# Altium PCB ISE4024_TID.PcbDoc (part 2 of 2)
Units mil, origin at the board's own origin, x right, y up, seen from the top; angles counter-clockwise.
Board outline 5000 x 4000 mil, 4 copper layers (Layer 1 - CIN1 - Top Layer, Layer 2 - SHLD1 - GND, Layer 3 - SHLD2 - PWR, Layer 4 - CIN2 - Bottom Layer), stack 61.434 mil thick; 132 components, 87 nets, 388 pads, 164 vias.

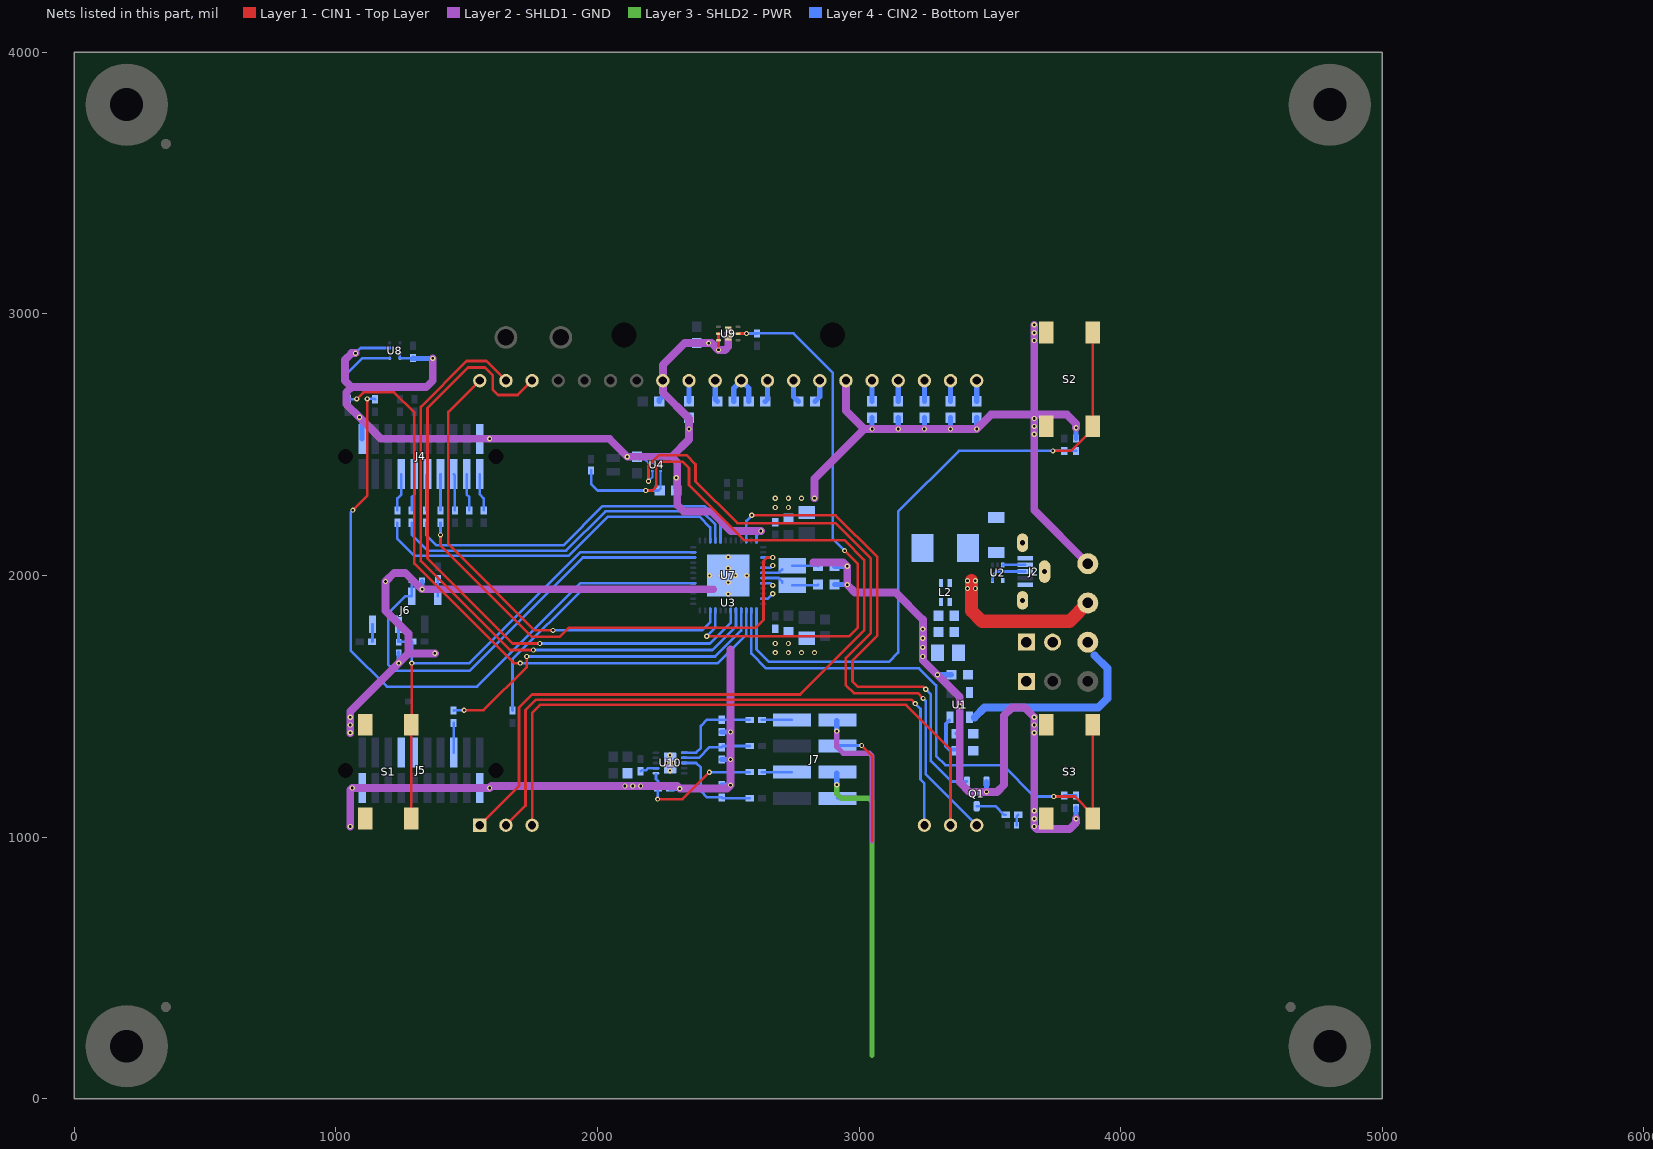
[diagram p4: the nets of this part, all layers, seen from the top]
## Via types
v1: diameter 20, hole 10, Layer 1 - CIN1 - Top Layer to Layer 4 - CIN2 - Bottom Layer, 151 vias
v2: diameter 19.68, hole 7.87, Layer 1 - CIN1 - Top Layer to Layer 4 - CIN2 - Bottom Layer, 13 vias

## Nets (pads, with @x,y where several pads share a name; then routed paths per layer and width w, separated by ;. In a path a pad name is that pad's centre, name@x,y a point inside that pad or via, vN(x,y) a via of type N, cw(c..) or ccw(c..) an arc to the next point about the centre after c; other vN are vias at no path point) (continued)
GND: C2.2 C3.2 C4.2 C6.2 C7.2 C9.2 C10.2 C12.2 C13.2 C14.2 C15.2 C16.2 C17.1 C18.1 C19.2 C20.1 C21.1 C22.2 C23.1 C24.1 C25.1 C26.2 C27.2 C28.1 C29.2 C30.2 C31.1 C32.1 C33.2 C34.1 C35.1 J4.2 J4.20 J5.1 J5.19 J6.5 L3.2 Q1.2 S1.3 S1.4 S2.3 S2.4 S3.3 S3.4 TP4.1 U1.2 U3.26 U3.33 U4.B3 U4.C2 U5.2 U6.2 U7.36 U7.41 U7.44 U7.47 U7.49 U8.B2 U8.C1 U8.D1 U9.2 U9.3 U9.7 U10.7 U10.11 | length 14443.8
  Layer 1 - CIN1 - Top Layer w10: v1(2462.6,2862.4) U9.3@2462.6,2899.21 U9.2@2462.6,2925
  Layer 2 - SHLD1 - GND w30: v1(1055,1040) 1055,1180 v1(1062.48,1187.48) v1(1587.52,1187.48) 1595.04,1195 v1(2105,1195) v1(2135,1195) v1(2165,1195) 2305,1195 v1(2315,1185) 2495,1185 v1(2508.62,1198.62) v1(2508.62,1296.38) v1(2508.62,1401.38) 2508.62,1716.38 ; v1(1055,1398.27) v1(1055,1428.27) v1(1055,1458.27) 1055,1480 v1(1240,1665) 1277.3,1702.3 ; v1(1075,2850) 1060,2850 1035,2825 1035,2745 1060,2720 ; v1(1370,2830) 1370,2745 1345,2720 1060,2720 ; v1(1378.38,1702.3) 1277.3,1702.3 ; 2442.13,1947.13 v1(1329.37,1947.13) 1327.87,1947.13 1265,2010 1222.87,2010 v1(1189.69,1976.81) 1189.69,1865.31 1277.3,1777.7 1277.3,1702.3 ; v2(2500,2925) 2500,2875 2487.4,2862.4 v1(2462.6,2862.4) 2436.5,2888.5 v1(2425,2888.5) 2333.5,2888.5 2250,2805 U3.33@2250,2745 2250,2700 2350,2600 v1(2350,2560) 2350,2520 2284,2454 ; v1(2625,2170) 2510,2170 2435,2245 2330,2245 2305,2270 2305,2433 2284,2454 ; 2825,2050 2940,2050 v1(2955,2035) v1(2955,1965) 2985,1935 3140,1935 3244,1831 v1(3244,1795) v1(3244,1760) v1(3244,1725) v1(3244,1690) 3244,1676.01 3385,1535.01 v1(3385,1500) 3385,1209.32 3421.91,1172.4 v1(3487.4,1172.4) 3527.4,1172.4 3555,1200 3555,1465 3585,1495 3633.27,1495 v1(3670,1458.27) v1(3670,1428.27) v1(3670,1398.27) v1(3670,1100) v1(3670,1070) v1(3670,1040) 3680.01,1030 3805,1030 3830,1055 v1(3830,1070) ; v1(2830,2295) 2830,2370 3020,2560 ; U3.26@2950,2745 2950,2630 3020,2560 ; v1(3670,2958.27) v1(3670,2928.27) v1(3670,2898.27) 3670,2615 ; v1(3830,2565) 3830,2580 3795,2615 3670,2615 ; TP4.1@3875,2045 3670,2250 v1(3670,2540) v1(3670,2570) v1(3670,2600) 3670,2615 ; 1060,2720 1040,2700 1040,2655 v1(1090,2605) 1172.48,2522.52 v1(1587.52,2522.52) 2045.48,2522.52 v1(2114,2454) 2284,2454 ; 3020,2560 v1(3050,2560) v1(3150,2560) v1(3250,2560) v1(3350,2560) v1(3450,2560) 3505,2615 3670,2615
  Layer 4 - CIN2 - Bottom Layer w4: U4.B3@2210,2430.75 U4.C2@2225.75,2415
  Layer 4 - CIN2 - Bottom Layer w8: C7.2@2160.12,2445 2180,2445 2194.25,2430.75 U4.B3@2210,2430.75
  Layer 4 - CIN2 - Bottom Layer w10: v1(1075,2850) 1094.85,2869.85 U8.B2@1205.31,2869.85 ; U8.C1@1244.68,2850.16 U8.D1@1244.68,2830.48 C28.1@1289.09,2830.48 ; C28.1@1289.09,2825.48 C28.1@1295,2831.38 ; C7.2@2150.75,2454.37 C7.2@2160.12,2445 ; C31.1@2165,1251.38 2168.62,1255 2185,1255 2193.32,1263.32 U10.7@2232,1263.32 ; U7.36@2608.27,2127 U7.36@2608.27,2133.86 2608.27,2153.27 v1(2625,2170) ; U7.47@2627,1911.42 2651.42,1911.42 v1(2670,1930) ; U7.44@2627,1970.47 2661.53,1970.47 v1(2670,1962) ; U7.41@2627,2029.53 2661.53,2029.53 v1(2670,2038)
  Layer 4 - CIN2 - Bottom Layer w15: v1(1240,1665) U6.2@1240,1705.32 ; C3.2@3373.5,1395 3385,1406.5 U1.2@3385,1457.76 v1(3385,1500)
  Layer 4 - CIN2 - Bottom Layer w20: v1(1062.48,1187.48) J5.19@1100,1187.48 ; v1(1090,2605) 1100,2595 J4.20@1100,2522.52 ; J6.5@1189.69,1919.96 v1(1189.69,1976.81) ; C28.1@1295,2831.38 1296.38,2830 v1(1370,2830) ; v1(1329.37,1947.13) U5.2@1329.37,1976.81 ; C23.1@1338.62,1702.3 v1(1378.38,1702.3) ; J5.1@1550,1187.48 v1(1587.52,1187.48) ; J4.2@1550,2522.52 v1(1587.52,2522.52) ; v1(2114,2454) 2150.38,2454 C7.2@2150.75,2454.37 ; C6.2@2236.5,2665 2236.5,2671.5 2250,2685 U3.33@2250,2745 ; C35.1@2278.62,1185 v1(2315,1185) ; C16.2@2301.5,2335 v1(2301.5,2373.5) ; v1(2350,2560) C9.2@2350,2603.5 ; C34.1@2475,1198.62 v1(2508.62,1198.62) ; C32.1@2475,1296.38 v1(2508.62,1296.38) ; C33.2@2475,1401.38 v1(2508.62,1401.38) ; C27.2@2906.5,1965 v1(2955,1965) ; C26.2@2906.5,2035 v1(2955,2035) ; v1(3050,2560) C10.2@3050,2603.5 ; v1(3150,2560) C12.2@3150,2603.5 ; v1(3250,2560) C13.2@3250,2603.5 ; v1(3300,1620) C4.2@3353.5,1620 ; v1(3350,2560) C14.2@3350,2603.5 ; v1(3450,2560) C15.2@3450,2603.5 ; v1(3487.4,1172.4) Q1.2@3487.4,1212.24 ; v1(3830,1070) C25.1@3830,1111.38 ; C24.1@3830,2523.62 v1(3830,2565)
  Layer 4 - CIN2 - Bottom Layer w25: C29.2@2380,2888.5 v1(2425,2888.5)
  other v1: 2680,1705 2730,1705 2780,1705 2830,1705 2680,1740 2730,1740 2680,2260 2730,2260 2680,2295 2730,2295 2780,2295
  other v2: 2277.82,1253.47 2264.04,1283 2291.6,1283 2277.82,1312.53 2500,1929.13 2500,1972.44 2429.13,2000 2472.44,2000 2527.56,2000 2570.87,2000 2500,2027.56 2500,2070.87
HDC_DRDY: R23.1 U7.3 U8.D2 | length 2730.7
  Layer 1 - CIN1 - Top Layer w10: v1(1080,2675) 1105,2700 1222.5,2700 1300,2622.5 1300,2045 1680,1665 v1(1705,1665)
  Layer 4 - CIN2 - Bottom Layer w10: v1(1080,2675) 1078.62,2673.62 R23.1@1045,2673.62 1045,2775 1100.48,2830.48 U8.D2@1205.31,2830.48 ; v1(1705,1665) 2460,1665 2568.9,1773.9 U7.3@2568.9,1873
HFXIN: C26.1 U7.42 Y1.1 | length 183.9
  Layer 4 - CIN2 - Bottom Layer w10: U7.42@2627,2009.84 2692.84,2009.84 Y1.1@2706,2023 ; Y1.1@2745,2037.4 2841.1,2037.4 C26.1@2843.5,2035
HFXOUT: C27.1 U7.43 Y1.2 | length 187.9
  Layer 4 - CIN2 - Bottom Layer w10: U7.43@2627,1990.16 2692.84,1990.16 2706,1977 Y1.2@2706,1973 ; Y1.2@2745,1962.6 2841.1,1962.6 C27.1@2843.5,1965
ILED: U3.20 U4.D3 | length 2583.7
  Layer 1 - CIN1 - Top Layer w10: v1(2195,2360) 2195,2420.06 2234.94,2460 2340,2460 2375,2425 2375,2360 2535,2200 2910,2200 3045,2065 3045,1780 2950,1685 2950,1580 2980,1550 3225,1550 v1(3245,1530)
  Layer 4 - CIN2 - Bottom Layer w8: v1(2195,2360) 2210,2375 U4.D3@2210,2399.25
  Layer 4 - CIN2 - Bottom Layer w10: v1(3245,1530) 3255,1520 3255,1240 U3.20@3450,1045
LCD_A0: U3.38 U7.6 | length 2518.4
  Layer 1 - CIN1 - Top Layer w10: U3.38@1750,2745 1695,2690 1620,2690 1600,2710 1600,2765 1570,2795 1505,2795 1350,2640 1350,2065 1675,1740 v1(1780,1740)
  Layer 4 - CIN2 - Bottom Layer w10: v1(1780,1740) 2430,1740 2509.84,1819.84 U7.6@2509.84,1873
LED_1: Q1.1 U7.34 | length 1917.9
  Layer 1 - CIN1 - Top Layer w10: v1(2590,2230) 2910,2230 3070,2070 3070,1770 2975,1675 2975,1595 2995,1575 3245,1575 v1(3255,1565)
  Layer 4 - CIN2 - Bottom Layer w10: U7.34@2568.9,2127 2568.9,2208.9 v1(2590,2230) ; v1(3255,1565) 3275,1545 3275,1290 3352.76,1212.24 Q1.1@3412.6,1212.24
LED_CA1: U3.2 U3.18 | length 2463.3
  Layer 1 - CIN1 - Top Layer w10: U3.2@1650,1045 1725,1120 1725,1485 1765,1525 3200,1525 v1(3215,1510)
  Layer 4 - CIN2 - Bottom Layer w10: v1(3215,1510) 3235,1490 3235,1220 3250,1205 U3.18@3250,1045
LED_CA2: U3.3 U3.19 | length 2402.8
  Layer 1 - CIN1 - Top Layer w10: U3.3@1750,1045 1750,1475 1780,1505 3180,1505 3350,1335 U3.19@3350,1045
NCSB_LCD: U3.40 U7.10 | length 1877.3
  Layer 1 - CIN1 - Top Layer w10: U3.40@1550,2745 1430,2625 1430,2120 1760,1790 v1(1830,1790)
  Layer 4 - CIN2 - Bottom Layer w10: v1(1830,1790) 2400,1790 2431.1,1821.1 U7.10@2431.1,1873
NCSB_RF: R12.2 U7.39 | length 1802
  Layer 1 - CIN1 - Top Layer w10: v1(1400,2155) 1400,2115 1750,1765 1855,1765 1890,1800 2605,1800 2635,1830 2635,2055 2648.9,2068.9 v1(2670,2068.9)
  Layer 4 - CIN2 - Bottom Layer w10: v1(1400,2155) R12.2@1400,2201.38 ; U7.39@2627,2068.9 U7.39@2633.86,2068.9 v1(2670,2068.9)
NetC2_1: C2.1 J1.1 L1.2
NetC4_1: C4.1 J3.1 U1.5
NetC5_1: C5.1 U3.31 | length 83.5
  Layer 4 - CIN2 - Bottom Layer w20: U3.31@2450,2745 2450,2673.5 C5.1@2458.5,2665
NetC5_2: C5.2 C8.1 U3.30 | length 183.6
  Layer 4 - CIN2 - Bottom Layer w20: C5.2@2521.5,2665 2521.5,2716.5 U3.30@2550,2745 2578.5,2716.5 C8.1@2578.5,2665
NetC8_2: C8.2 U3.29 | length 83.5
  Layer 4 - CIN2 - Bottom Layer w20: C8.2@2641.5,2665 2650,2673.5 U3.29@2650,2745
NetC9_1: C9.1 U3.32 | length 78.5
  Layer 4 - CIN2 - Bottom Layer w20: C9.1@2350,2666.5 U3.32@2350,2745
NetC10_1: C10.1 U3.25 | length 78.5
  Layer 4 - CIN2 - Bottom Layer w20: C10.1@3050,2666.5 U3.25@3050,2745
NetC11_1: C11.1 U3.28 | length 87.7
  Layer 4 - CIN2 - Bottom Layer w20: U3.28@2750,2745 2750,2683.5 C11.1@2768.5,2665
NetC11_2: C11.2 U3.27 | length 87.7
  Layer 4 - CIN2 - Bottom Layer w20: C11.2@2831.5,2665 2850,2683.5 U3.27@2850,2745
NetC12_1: C12.1 U3.24 | length 78.5
  Layer 4 - CIN2 - Bottom Layer w20: C12.1@3150,2666.5 U3.24@3150,2745
NetC13_1: C13.1 U3.23 | length 78.5
  Layer 4 - CIN2 - Bottom Layer w20: C13.1@3250,2666.5 U3.23@3250,2745
NetC14_1: C14.1 U3.22 | length 78.5
  Layer 4 - CIN2 - Bottom Layer w20: C14.1@3350,2666.5 U3.22@3350,2745
NetC15_1: C15.1 U3.21 | length 78.5
  Layer 4 - CIN2 - Bottom Layer w20: C15.1@3450,2666.5 U3.21@3450,2745
NetC32_2: C32.2 R24.2 U10.2 | length 276.6
  Layer 4 - CIN2 - Bottom Layer w10: U10.2@2324,1302.69 2387.69,1302.69 2428.62,1343.62 C32.2@2475,1343.62 2479.38,1348 R24.2@2581.88,1348
NetC33_1: C33.1 R25.1 U10.1 | length 360.2
  Layer 4 - CIN2 - Bottom Layer w10: U10.1@2324,1322.37 2377.37,1322.37 2395,1340 2395,1425 2418.62,1448.62 C33.1@2475,1448.62 2475.62,1448 R25.1@2581.88,1448
NetC34_2: C34.2 R26.2 U10.3 | length 366.5
  Layer 4 - CIN2 - Bottom Layer w10: U10.3@2324,1283 2377,1283 2395,1265 2395,1175 2418.62,1151.38 C34.2@2475,1151.38 2478.38,1148 R26.2@2581.88,1148
NetC35_2: C35.2 R27.1 U10.6 | length 493.3
  Layer 1 - CIN1 - Top Layer w10: v1(2230,1145) 2325,1145 v1(2428,1248)
  Layer 4 - CIN2 - Bottom Layer w10: U10.6@2223.69,1240 2223.69,1221.31 2231.38,1213.62 C35.2@2231.38,1185 2230,1183.62 v1(2230,1145) ; v1(2428,1248) R27.1@2581.88,1248
NetD3_1: D3.1 J5.12 J5.14
NetD4_1: D4.1 R21.2 | length 42.4
  Layer 4 - CIN2 - Bottom Layer w10: D4.1@3602.72,1045 3602.72,1079.09 R21.2@3608.62,1085
NetJ4_1: J4.1 R15.2 | length 145.1
  Layer 4 - CIN2 - Bottom Layer w10: J4.1@1550,2387.48 1550,2310 1565,2295 R15.2@1565,2248.62
NetJ4_3: J4.3 R14.1 | length 143
  Layer 4 - CIN2 - Bottom Layer w10: J4.3@1500,2387.48 1500,2310 1510,2300 R14.1@1510,2248.62
NetJ4_5: J4.5 R13.1 | length 140.9
  Layer 4 - CIN2 - Bottom Layer w10: J4.5@1450,2387.48 1455,2382.48 R13.1@1455,2248.62
NetJ4_7: J4.7 R12.1 | length 138.9
  Layer 4 - CIN2 - Bottom Layer w10: R12.1@1400,2248.62 J4.7@1400,2387.48
NetJ4_9: J4.9 R8.2 | length 140.9
  Layer 4 - CIN2 - Bottom Layer w10: R8.2@1345,2248.62 1345,2382.48 J4.9@1350,2387.48
NetJ4_11: J4.11 R7.2 | length 143
  Layer 4 - CIN2 - Bottom Layer w10: R7.2@1290,2248.62 1290,2300 1300,2310 J4.11@1300,2387.48
NetJ4_13: J4.13 R5.1 | length 145.1
  Layer 4 - CIN2 - Bottom Layer w10: R5.1@1235,2248.62 1235,2295 1250,2310 J4.13@1250,2387.48
NetJ5_6: J5.6 R11.1 | length 113.9
  Layer 4 - CIN2 - Bottom Layer w10: J5.6@1450,1322.52 R11.1@1450,1436.38
NetJ6_1: J6.1 R3.2 | length 73.2
  Layer 4 - CIN2 - Bottom Layer w10: J6.1@1389.69,1919.96 R3.2@1389.69,1993.19
NetJ6_6: J6.6 R9.2 | length 67.4
  Layer 4 - CIN2 - Bottom Layer w10: R9.2@1138.31,1746.81 1139.69,1748.19 J6.6@1139.69,1813.66
NetL1_1: L1.1 L2.3
NetL2_2: L2.2 L3.1
NetQ1_3: Q1.3 R21.1 | length 124.9
  Layer 4 - CIN2 - Bottom Layer w10: Q1.3@3450,1117.76 3522.24,1117.76 3555,1085 R21.1@3561.38,1085
NetR1_2: R1.2 U1.3 | length 148.4
  Layer 4 - CIN2 - Bottom Layer w15: U1.3@3345,1445 3333,1433 3333,1347 3345,1335 R1.2@3373.5,1335
NRST_EM: R11.2 U7.4 | length 1333
  Layer 1 - CIN1 - Top Layer w10: v1(1490,1485) 1565,1485 1730,1650 v1(1730,1690)
  Layer 4 - CIN2 - Bottom Layer w10: R11.2@1450,1483.62 1451.38,1485 v1(1490,1485) ; v1(1730,1690) 2450,1690 2549.21,1789.21 U7.4@2549.21,1873
NRST_LCD: U3.39 U7.5 | length 2469.5
  Layer 1 - CIN1 - Top Layer w10: U3.39@1650,2745 1575,2820 1500,2820 1325,2645 1325,2055 1665,1715 v1(1755,1715)
  Layer 4 - CIN2 - Bottom Layer w10: v1(1755,1715) 2440,1715 2529.53,1804.53 U7.5@2529.53,1873
OPT_INT: R22.1 U7.9 U9.5 | length 2149.8
  Layer 1 - CIN1 - Top Layer w10: v1(2417.5,1767.5) 2962.5,1767.5 2995,1800 2995,2045 v1(2945,2095) ; U9.5@2537.4,2925 v1(2570,2925)
  Layer 4 - CIN2 - Bottom Layer w10: v1(2417.5,1767.5) 2450.79,1800.79 U7.9@2450.79,1873 ; v1(2570,2925) 2609.39,2925 R22.1@2610,2925.61 2749.39,2925.61 2900,2775 2900,2140 v1(2945,2095)
OVP: C16.1 D2.1 U3.1 U4.D1 | length 3739.6
  Layer 1 - CIN1 - Top Layer w10: U3.1@1550,1045 1700,1195 1700,1495 1750,1545 2775,1545 3020,1790 3020,2060 2945,2135 2560,2135 2350,2345 2350,2410 2325,2435 2245,2435 2225,2415 2225,2340 2210,2325 v1(2185,2325)
  Layer 4 - CIN2 - Bottom Layer w8: C16.1@2241.5,2332.99 U4.D1@2241.5,2399.25
  Layer 4 - CIN2 - Bottom Layer w10: D2.1@1975.75,2401.22 1975.75,2349.25 2000,2325 v1(2185,2325) 2233.5,2325 C16.1@2241.5,2332.99
P3.4: R5.2 U7.27 | length 1420.5
  Layer 4 - CIN2 - Bottom Layer w10: R5.2@1235,2201.38 1235,2140 1300,2075 1890,2075 2040,2225 2390,2225 2431.1,2183.9 U7.27@2431.1,2127
P3.5: R7.1 U7.28 | length 1382.4
  Layer 4 - CIN2 - Bottom Layer w10: R7.1@1290,2201.38 1290,2155 1350,2095 1880,2095 2030,2245 2400,2245 2450.79,2194.21 U7.28@2450.79,2127
P3.6: R8.1 U7.29 | length 1353.1
  Layer 4 - CIN2 - Bottom Layer w10: R8.1@1345,2201.38 1345,2155 1385,2115 1870,2115 2020,2265 2410,2265 2470.47,2204.53 U7.29@2470.47,2127
SBWTCK: J6.3 U5.1 U7.22 | length 1736.7
  Layer 4 - CIN2 - Bottom Layer w10: U5.1@1290,1981.81 1289.69,1981.5 J6.3@1289.69,1919.96 1264.96,1919.96 1200,1855 1200,1660 1225,1635 1510,1635 1943.9,2068.9 U7.22@2373,2068.9
SBWTDIO: C23.2 J6.4 R18.1 S1.1 S1.2 U6.1 U7.23 | length 2055.2
  Layer 1 - CIN1 - Top Layer w10: S1.2@1288.58,1070.87 S1.1@1288.58,1429.13 1290,1430.55 v1(1290,1665)
  Layer 4 - CIN2 - Bottom Layer w10: J6.4@1239.69,1813.66 1239.37,1813.35 1239.37,1746.81 1239.86,1747.3 R18.1@1291.38,1747.3 C23.2@1291.38,1702.3 1290,1700.92 v1(1290,1665) 1510,1665 1933.58,2088.58 U7.23@2373,2088.58
SENSOR1: J7.3 | length 474.5
  Layer 1 - CIN1 - Top Layer w10: v1(3010,1350) 3050,1310 3050,985
  Layer 4 - CIN2 - Bottom Layer w10: J7.3@2917.9,1348 2919.9,1350 v1(3010,1350)
SENSOR2: J7.7 | length 1092.5
  Layer 4 - CIN2 - Bottom Layer w10: J7.7@2917.9,1148 3037,1148 3050,1135 3050,180
SHLD1: J7.2 R25.2 | length 114
  Layer 4 - CIN2 - Bottom Layer w10: R25.2@2629.12,1448 J7.2@2743.1,1448
SHLD1_1: J7.1 | length 578.7
  Layer 2 - SHLD1 - GND w20: v1(2915,1405) 2915,1345 2940,1320 3040,1320 3050,1310 3050,985
  Layer 4 - CIN2 - Bottom Layer w10: J7.1@2915,1445.1 J7.1@2917.9,1448
  Layer 4 - CIN2 - Bottom Layer w20: v1(2915,1405) J7.1@2915,1445.1
SHLD1_2: J7.5 | length 1201.6
  Layer 3 - SHLD2 - PWR w20: v1(2915,1200) 2915,1165 2932,1148 3037,1148 3050,1135 3050,165
  Layer 4 - CIN2 - Bottom Layer w10: J7.5@2915,1245.1 J7.5@2917.9,1248
  Layer 4 - CIN2 - Bottom Layer w20: v1(2915,1200) J7.5@2915,1245.1
SHLD2: J7.6 R27.2 | length 114
  Layer 4 - CIN2 - Bottom Layer w10: R27.2@2629.13,1248 J7.6@2743.1,1248
UART_CTS: R2.2 U7.17 | length 2556.5
  Layer 1 - CIN1 - Top Layer w10: v1(1065,2250) 1120,2305 v1(1120,2675)
  Layer 4 - CIN2 - Bottom Layer w10: v1(1065,2250) 1056,2241 1056,1714 1195,1575 1540,1575 1935.47,1970.47 U7.17@2373,1970.47 ; v1(1120,2675) 1148.62,2675 R2.2@1150,2673.62
UART_RTS: R10.1 U7.16 | length 1006.5
  Layer 4 - CIN2 - Bottom Layer w10: R10.1@1675,1483.62 1675,1680 1945.79,1950.79 U7.16@2373,1950.79
USB_D_N: J2.2 U2.3 | length 85.8
  Layer 4 - CIN2 - Bottom Layer w10: U2.3@3549.69,2039.53 3550.75,2040.59 J2.2@3635,2040.59
USB_D_P: J2.3 U2.5 | length 150.6
  Layer 4 - CIN2 - Bottom Layer w10: U2.5@3510.31,1980.47 3510.31,2000.31 3525,2015 J2.3@3635,2015
USB_GND: C1.2 D1.1 J2.5 J2.6 J2.7 J2.8 L2.1 U2.4
USR_BTN_1: C24.2 R19.1 S2.1 S2.2 U7.1 | length 2604.5
  Layer 1 - CIN1 - Top Layer w10: v1(3741.38,2476.38) 3811.38,2476.38 3893.58,2558.58 S2.2@3893.58,2570.86 S2.1@3893.58,2929.13
  Layer 4 - CIN2 - Bottom Layer w10: U7.1@2608.27,1873 2608.27,1716.73 2655,1670 3115,1670 3150,1705 3150,2245 3381.38,2476.38 v1(3741.38,2476.38) R19.1@3785,2476.38 C24.2@3830,2476.38
USR_BTN_2: C25.2 R20.1 S3.1 S3.2 U7.2 | length 2334.3
  Layer 1 - CIN1 - Top Layer w10: v1(3745,1155) 3825,1155 S3.2@3893.58,1086.42 ; S3.2@3893.58,1070.87 S3.2@3893.58,1086.42 ; S3.1@3893.58,1429.13 S3.2@3893.58,1086.42
  Layer 4 - CIN2 - Bottom Layer w10: U7.2@2588.58,1873 2588.58,1701.42 2645,1645 3230,1645 3295,1580 3295,1310 3330,1275 3550,1275 3670,1155 v1(3745,1155) 3781.38,1155 R20.1@3785,1158.62 C25.2@3830,1158.62
V_INPUT: C3.1 J1.2 R1.1 TP2.1 U1.1 | length 723.3
  Layer 4 - CIN2 - Bottom Layer w30: 3442.49,1457.49 3480,1495 3915,1495 3950,1530 3950,1645 3900,1695
VBUS: C1.1 D1.2 J2.1 L2.4 TP1.1 | length 605.6
  Layer 1 - CIN1 - Top Layer w50: 3430,1980 3430,1865 3470,1825 3805,1825 TP1.1@3875,1895
  other v1: 3415,1950 3445,1950 3415,1980 3445,1980
pads on no net: FID1.1 FID2.1 FID3.1 FID4.1 FID5.1 FID6.1 H1.1 H2.1 H3.1 H4.1 H5.0 H6.0 H7.0 H8.0 J2.4 J4.4 J4.6 J4.8 J4.10 J4.15 J4.16 J4.17 J4.19 J4.MH1 J4.MH2 J5.2 J5.4 J5.5 J5.7 J5.8 J5.9 J5.10 J5.11 J5.13 J5.15 J5.16 J5.17 J5.18 J5.20 J5.MH1 J5.MH2 SH-J1.0 SH-J2.0 SH-J3.0 SH-J4.0 SH-J5.0 SH-J6.0 U1.4 U2.1 U2.2 U4.B2 U4.D2 U7.8 U7.12 U7.13 U7.14 U7.15 U7.18 U7.19 U7.30 U7.33 U7.35 U7.38 U7.40 U7.45 U7.46 U8.C2 U10.4 U10.5

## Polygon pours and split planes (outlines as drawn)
NetC4_1 on Layer 4 - CIN2 - Bottom Layer "Layer 1 - CIN1 - Top Layer-No Net" (solid, remove dead copper, pour order 13): 3655,1645 3390,1645 3390,1545 3410,1525 3655,1525 3675,1545 3675,1625
GND on Layer 2 - SHLD1 - GND "Layer 2 - SHLD1 - GND-GND" (solid, remove dead copper, pour order 5): 3005,1655 2375,1655 2375,2310 3005,2310

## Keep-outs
Keep-Out Layer:
  text ".Layer_Name" at 577,-858.49 h60

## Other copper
Layer 1 - CIN1 - Top Layer:
  region net SENSOR1: 400,0 400,400 1000,400 1000,1000 4000,1000 4000,3000 1000,3000 1000,400 0,400 0,3600 400,3600 400,4000 4600,4000 4600,3600 5000,3600 5000,400 4600,400 4600,0
  region net GND: 3745,2525 3655,2525 3655,2615 3745,2615
  region net GND: 3745,2883.27 3655,2883.27 3655,2973.27 3745,2973.27
  region net GND: 3745,1025 3655,1025 3655,1115 3745,1115
  region net GND: 1140,1383.27 1040,1383.27 1040,1473.27 1140,1473.27
  region net GND: 1140,1025 1040,1025 1040,1115 1140,1115
  region net GND: 3745,1383.27 3655,1383.27 3655,1473.27 3745,1473.27
  text ".Layer_Name" at 577,-858.49 h60
Layer 2 - SHLD1 - GND:
  region net SHLD1_1: 400,0 400,400 1000,400 1000,1000 4000,1000 4000,3000 1000,3000 1000,400 0,400 0,3600 400,3600 400,4000 4600,4000 4600,3600 5000,3600 5000,400 4600,400 4600,0
  region net GND: 2250,1195 2250,1325 2325,1325 2325,1195
Layer 3 - SHLD2 - PWR:
  region net SHLD1_2: 400,0 4600,0 4600,400 5000,400 5000,3600 4600,3600 4600,4000 400,4000 400,3600 0,3600 0,400 400,400 400,200 600,200 600,600 200,600 200,3400 600,3400 600,3800 4400,3800 4400,3400 4800,3400 4800,600 4400,600 4400,200 600,200 400,200
  region net 3P3V: 3700,1545 3700,1625 3720,1645 3900,1645 3920,1625 3920,1545 3900,1525 3720,1525
Layer 4 - CIN2 - Bottom Layer:
  region net SENSOR2: 400,0 4600,0 4600,400 5000,400 5000,3600 4600,3600 4600,4000 400,4000 400,3600 0,3600 0,400 400,400 400,200 600,200 600,600 200,600 200,3400 600,3400 600,3800 4400,3800 4400,3400 4800,3400 4800,600 4400,600 4400,200 600,200 400,200
  region net USB_GND: 3535,1990 3571,1990 3593,1968 3678,1968 3685,1975 3685,2075 3675,2085 3615,2085 3600,2100 3600,2155 3570,2185 3355,2185 3322,2152 3322,1947 3310,1935 3212,1935 3200,1947 3200,2225 3280,2305 3660,2305 3755,2210 3755,1890 3725,1860 3550,1860 3535,1875
  region net NetL1_1: 3338,1825 3385,1825 3385,1895 3360,1920 3338,1920
  region net NetL2_2: 3325,1825 3285,1825 3285,1895 3310,1920 3325,1920
  region net GND: 3324,1805 3324,1675 3229,1675 3229,1805
  region net NetD3_1: 1235,1265 1315,1265 1315,1425 1290,1450 1260,1450 1235,1425
  region net AVCC: 2622,1897 2622,1868 2665,1825 2750,1825 2775,1800 2890,1800 2890,1910 2673,1910 2660,1897
  region net GND: 2665,1815 2740,1815 2770,1785 2840,1785 2840,1690 2675,1690 2665,1700
  region net 3P3V: 2622,2103 2622,2132 2665,2175 2750,2175 2775,2200 2840,2200 2840,2090 2673,2090 2660,2103
  region net GND: 2665,2185 2740,2185 2770,2215 2840,2215 2840,2310 2675,2310 2665,2300
  region net 3P3V: 3700,1545 3700,1625 3720,1645 3900,1645 3920,1625 3920,1545 3900,1525 3720,1525
  region net GND: 2095,1185 2095,1270 2177,1270 2177,1185
  region net 3P3V: 2195,2645 2195,2750 2170,2775 2025,2775 2005,2755 2005,2665 2025,2645
  region net 3P3V: 2035,2415 2090,2415 2090,2350 2035,2350
  region net 3P3V: 1260,1500 1270,1490 1340,1490 1340,1555 1270,1555 1260,1545
  region net NetC2_1: 3345,1805 3345,1680 3360,1665 3655,1665 3675,1685 3675,1785 3655,1805
  region net VBUS: 3338,1947 3350,1935 3458,1935 3470,1947 3470,2047 3489,2066 3560,2066 3565.5,2060.5 3569,2057 3665,2057 3665,2075 3604,2075 3582,2097 3582,2140 3562,2160 3352,2160 3338,2146
  region net V_INPUT: 3700,1685 3700,1785 3720,1805 3900,1805 3925,1780 3925,1680 3910,1665 3720,1665
  region net V_INPUT: 3409,1316 3420,1305 3460,1305 3470,1315 3470,1464 3449,1485 3409,1485
  text ".Layer_Name" at 577,-858.49 h60

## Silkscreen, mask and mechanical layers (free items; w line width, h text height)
Top Overlay:
  text "USR_BTN" at 3650,3065 h75
  text "1" at 3790,2990 h75
  text "RESET" at 1095,965 h75
  text "USR_BTN" at 3650,965 h75
  text "2" at 3790,890 h75
  text "TIDA-00373" at 2225,225 h100
  text ".Layer_Name" at 577,-858.49 h60
Bottom Overlay:
  text "B0_SDA" at 1710,3000 h40
  text "B0_SCL" at 1920,3000 h40
  text "GND" at 4130,1990 h75
  text "VBUS" at 4170,1840 h75
  text "1" at 1424,1766 h40
  text "V_INPUT" at 4270,1690 h75
  text "3v3" at 4100,1540 h75
  text "SHLD1" at 3240,1430 h75
  text "CIN1" at 3240,1330 h75
  text "SHLD2" at 3240,1230 h75
  text "CIN2" at 3240,1130 h75
  text "2014" at 1950,175 h100
  text "©" at 2050,175 h105
  text "Rev. E2" at 2575,175 h100
  text "ISE4024" at 3125,175 h100
  text ".Layer_Name" at 577,-858.49 h60
Top Paste:
  text ".Layer_Name" at 577,-858.49 h60
Bottom Paste:
  text ".Layer_Name" at 577,-858.49 h60
Top Solder:
  text ".Layer_Name" at 577,-858.49 h60
  text ".Layer_Name" at 577,-858.49 h60
Bottom Solder:
  text ".Layer_Name" at 577,-858.49 h60
Drill Guide:
  text ".Layer_Name" at 577,-858.49 h60
M1 Board Outline:
  lines w10: -5,0 ccw(c0,0) 0,-5 ; -5,0 ccw(c0,0) 0,-5 ; -5,0 ccw(c0,0) 0,-5 ; -5,0 ccw(c0,0) 0,-5 ; -5,0 ccw(c0,0) 0,-5 ; -5,0 ccw(c0,0) 0,-5 ; -5,0 ccw(c0,0) 0,-5 ; -5,0 ccw(c0,0) 0,-5 ; -5,4000 cw(c0,4000) 0,4005 ; -5,4000 cw(c0,4000) 0,4005 ; -5,4000 cw(c0,4000) 0,4005 ; -5,4000 cw(c0,4000) 0,4005 ; -5,4000 cw(c0,4000) 0,4005 ; -5,4000 cw(c0,4000) 0,4005 ; -5,4000 cw(c0,4000) 0,4005 ; -5,4000 cw(c0,4000) 0,4005 ; 5000,-5 ccw(c5000,0) 5005,0 ; 5000,-5 ccw(c5000,0) 5005,0 ; 5000,-5 ccw(c5000,0) 5005,0 ; 5000,-5 ccw(c5000,0) 5005,0 ; 5000,-5 ccw(c5000,0) 5005,0 ; 5000,-5 ccw(c5000,0) 5005,0 ; 5000,-5 ccw(c5000,0) 5005,0 ; 5000,-5 ccw(c5000,0) 5005,0 ; 5000,4005 cw(c5000,4000) 5005,4000 ; 5000,4005 cw(c5000,4000) 5005,4000 ; 5000,4005 cw(c5000,4000) 5005,4000 ; 5000,4005 cw(c5000,4000) 5005,4000 ; 5000,4005 cw(c5000,4000) 5005,4000 ; 5000,4005 cw(c5000,4000) 5005,4000 ; 5000,4005 cw(c5000,4000) 5005,4000 ; 5000,4005 cw(c5000,4000) 5005,4000 ; 1135,2760 1135,2790 1315,2790 1315,2760 1135,2760 ; 1135,2945 1315,2945 1315,2975 1135,2975 1135,2945
  lines w20: -10,0 ccw(c0,0) 0,-10 ; -10,0 ccw(c0,0) 0,-10 ; -10,0 -10,4000 ; -10,4000 cw(c0,4000) 0,4010 ; -10,4000 cw(c0,4000) 0,4010 ; 0,-10 5000,-10 ; 0,4010 5000,4010 ; 5000,-10 ccw(c5000,0) 5010,0 ; 5000,-10 ccw(c5000,0) 5010,0 ; 5000,4010 cw(c5000,4000) 5010,4000 ; 5000,4010 cw(c5000,4000) 5010,4000 ; 5010,0 5010,4000 ; 0,0 0,4000 5000,4000 5000,0 0,0
  text ".Layer_Name" at 577,-858.49 h60
M2 Board Dimensions:
  rectangle: 0,-275 125,-150
  rectangle: 125,-400 500,-275
  lines w7: 0,-275 1000,-275 ; 125,-400 125,-150 ; 250,-400 250,-150 ; 500,-400 500,-150 ; 750,-400 750,-150 ; 0,-400 1000,-400 1000,-150 0,-150 0,-400
  text ".Layer_Name" at 577,-858.49 h60
M3 3D STEP Top:
  text ".Layer_Name" at 577,-858.49 h60
M4 3D STEP Bottom:
  text ".Layer_Name" at 577,-858.49 h60
M5 Assembly Top:
  lines w10: -292,-930.17 6308,-930.17 ; -292,-726.83 6310,-726.83 ; -292,-523.5 -292,-1133.5 3713,-1133.5 6310,-1133.5 6310,-523.5 -291.5,-523.5 -291.5,-1133.5 1284,-1133.5 ; 2173,-1133.5 2173,-523.5 ; 3440,-726.83 3440,-523.5 ; 4280,-726.83 4280,-523.5 ; 4902,-1140 4902,-937.17
  text "COMPONENTS MARKED 'DNP' SHOULD NOT BE POPULATED." at 1153.5,-318.5 h60
  text "ASSEMBLY VARIANT:" at 1153,-434 h60
  text ".VariantName" at 2189,-434 h60
  text "PCB VIEWED FROM TOP SIDE" at -228.5,-655.67 h60
  text "BOARD #:" at 2248,-655.67 h60
  text ".PRJ_Number" at 2793.5,-655.67 h60
  text "REV:" at 3638,-655.67 h60
  text ".PCB_Rev" at 3929.5,-655.67 h60
  text "SVN REV:" at 4476,-655.67 h60
  text ".VersionControl_RevNumber" at 4982,-655.67 h60
  text "PLOT NAME =" at -228.5,-1064.34 h60
  text ".plot_File_Name" at 577,-1064.34 h60
  text "GENERATED    :" at 2250,-1064.34 h60
  text ".Print_Date" at 3119.5,-1064.34 h60
  text ".Print_Time" at 3848.5,-1064.34 h60
  text "TEXAS INSTRUMENTS" at 5113,-1064.34 h60
M6 Assembly Bottom:
  lines w10: -292.5,-727.33 6309.5,-727.33 ; -290.5,-930.67 6309.5,-930.67 ; 1115.5,-1140.5 1115.5,-937.67 ; 1737.5,-727.33 1737.5,-524 ; 2577.5,-727.33 2577.5,-524 ; 3844.5,-1134 3844.5,-524 ; 4733.5,-1134 6309,-1134 6309,-524 -292.5,-524 -292.5,-1134 2304.5,-1134 6309.5,-1134 6309.5,-524
  text "COMPONENTS MARKED 'DNP' SHOULD NOT BE POPULATED." at 6102,-318 h60
  text ".VariantName" at 5058,-434 h60
  text "ASSEMBLY VARIANT:" at 6097,-434 h60
  text ".VersionControl_RevNumber" at 1035.5,-656.17 h60
  text "SVN REV:" at 1541.5,-656.17 h60
  text ".PCB_Rev" at 2088,-656.17 h60
  text "REV:" at 2379.5,-656.17 h60
  text ".PRJ_Number" at 3224,-656.17 h60
  text "BOARD #:" at 3769.5,-656.17 h60
  text "PCB VIEWED FROM BOTTOM SIDE" at 6246,-656.17 h60
  text "TEXAS INSTRUMENTS" at 904.5,-1064.84 h60
  text ".Print_Time" at 2169,-1064.84 h60
  text ".Print_Date" at 2898,-1064.84 h60
  text "GENERATED    :" at 3767.5,-1064.84 h60
  text ".plot_File_Name" at 5440.5,-1064.84 h60
  text "PLOT NAME =" at 6246,-1064.84 h60
M9 Title Sheet:
  drawing of 1178 lines, arcs and shapes, not listed
  text "1" at 739.84,8036.5 h70
  text "2" at 3235.5,8036.5 h70
  text "3" at 5724.84,8036.5 h70
  text "4" at 8231.51,8036.5 h70
  text "5" at 10730.5,8036.5 h70
  text "6" at 13235.5,8036.5 h70
  text "A" at -416.5,6893.5 h70
  text "A" at 14383.5,6893.5 h70
  text "B" at -416.5,4513.5 h70
  text "B" at 14383.5,4513.5 h70
  text "C" at -416.5,2138.5 h70
  text "C" at 14383.5,2138.5 h70
  text "PROJECT TITLE:" at 11343.5,277.5 h45
  text ".PRJ_Title" at 11393.5,144.17 h70
  text "DESIGNED FOR:" at 11343.5,-23.5 h45
  text ".PRJ_Customer" at 11393.5,-163.5 h70
  text "D" at -416.5,-231.5 h70
  text "D" at 14383.5,-231.5 h70
  text "FILE NAME:" at 11343.5,-323.5 h45
  text ".PCB_File_Name_No_Path" at 11393.5,-443.5 h70
  text "Texas Instruments (TI) and/or its licensors do not warrant the accuracy or completeness of this specification" at 6374,-605.34 h45
  text "ENGINEER:" at 11343.5,-613.5 h45
  text "LAYOUT BY:" at 12848.5,-613.5 h45
  text "or any information contained therein. TI and/or its licensors do not warrant that this design will meet" at 6329.01,-718 h45
  text ".PRJ_Engineer" at 11393.5,-768.49 h70
  text ".PCB_Layout" at 12899,-768.49 h70
  text "JMM" at 12850,-800 h100
  text "s  o  l  u  t  i  o  n  s" at 13708,-803 h68
  text "the specifications, will be suitable for your application or fit for any particular purpose, or will operate in" at 6329.01,-830.67 h45
  text ".Layer_Name" at 577,-858.49 h60
  text "ALTIUM DESIGNER VERSION:" at 12848.5,-923.5 h45
  text "an implementation. TI and/or its licensors do not warrant that the design is production worthy. You should" at 6329.01,-943.33 h45
  text "completely validate and test your design implementation to confirm the system functionality for your application." at 6374,-1056 h45
  text ".print_Scale" at 11393.5,-1056.83 h70
  text ".Application_BuildNumber" at 12899,-1056.83 h70
  text "1" at 739.84,-1263.5 h70
  text "2" at 3235.5,-1263.5 h70
  text "3" at 5724.84,-1263.5 h70
  text "4" at 8231.51,-1263.5 h70
  text "5" at 10730.5,-1263.5 h70
  text "6" at 13235.5,-1263.5 h70
M10 Fab Notes:
  drawing of 185 lines, arcs and shapes, not listed
  text "DESIGN INFORMATION" at 12381.02,5910 h60
  text "MIN. TRACK WIDTH:" at 11736.46,5730 h60
  text "8" at 12832.7,5730 h60
  text "MIL" at 12987.46,5730 h60
  text "MIN. CLEARANCE:" at 11736.46,5598 h60
  text "0.2" at 12772.7,5598 h60
  text "mm" at 12987.46,5598 h60
  text "MIN. VIA PAD SIZE:" at 11736.46,5466 h60
  text "24" at 12802.71,5466 h60
  text "MIL" at 12987.46,5466 h60
  text "0.05mm (2MIL)" at 12431.46,5324.29 h60
  text "MINIMUM ANNULAR RING" at 11407.23,5320 h60
  text "EXTERNAL" at 13139.46,5320 h60
  text "PER" at 11607.23,5202 h60
  text "IPC-D-275 CLASS 2 LEVEL C" at 11827.23,5202 h60
  text "MIL, HOLES" at 13315.46,5089.71 h60
  text "+/-" at 12923,5089 h60
  text "+/-" at 13777,5089 h60
  text "REGISTRATION TOLERANCES:" at 11407.23,5084 h60
  text "METAL" at 12607,5084 h60
  text "5" at 13183.2,5084 h60
  text "3" at 14016.2,5084 h60
  text "MIL" at 14132.46,5084 h60
  text "MATERIAL:" at 11332.46,4874.54 h60
  text "FR-4 High Tg" at 12318.9,4734.21 h60
  text "FR-408" at 11753.46,4725.64 h60
  text "X" at 12165.46,4725.64 h60
  text "OTHER" at 13241.46,4725.64 h60
  text "62 MIL (1.6mm) +/-10%" at 12073.56,4562.92 h60
  text "THICKNESS:" at 11407.23,4558.64 h60
  text "X" at 11945.4,4558.64 h60
  text "OTHER" at 13358.46,4558.64 h60
  text "TOLERANCE:" at 11407.23,4400.64 h60
  text "X" at 12246.53,4400.64 h60
  text "ANSI IPC-6012 TYPE 3 CLASS 2" at 12433.48,4400.64 h60
  text "OTHER +/-" at 12433.46,4244.64 h60
  text "BOW & TWIST:" at 11407.23,4087.64 h60
  text "X" at 12246.53,4087.64 h60
  text "ANSI IPC-6012 TYPE 3 CLASS 2" at 12433.48,4087.64 h60
  text "OTHER +/-" at 12433.46,3929.13 h60
  text "DRILLING:" at 11332.46,3790.64 h60
  text "REFERENCE:" at 11407.23,3673.64 h60
  text "X" at 12055.46,3673.64 h60
  text "AS SHOWN" at 12242.46,3673.64 h60
  text "X" at 12956.46,3673.64 h60
  text "NC_DRILL FILES" at 13093.46,3673.64 h60
  text "PTH MIN COPPER THICKNESS:" at 11407.23,3515.64 h60
  text "X" at 12757.46,3515.64 h60
  text "1MIL" at 12894.46,3515.64 h60
  text "OTHER" at 13391.46,3515.64 h60
  text "BOARD FINISH:" at 11332.46,3356.64 h60
  text "SILKSCREEN:" at 11487.68,3238.64 h60
  text "X" at 12436.46,3238.64 h60
  text "TOP" at 12562.46,3238.64 h60
  text "X" at 12946.46,3238.64 h60
  text "BOTTOM" at 13073.46,3238.64 h60
  text "SILKSCREEN COLOR:" at 11487.68,3071.64 h60
  text "X" at 12435.42,3071.64 h60
  text "WHITE" at 12562.46,3071.64 h60
  text "OTHER" at 13073.46,3071.64 h60
  text "SOLDER RESIST COLOR:" at 11487.68,2901.64 h60
  text "GREEN" at 12182.46,2742.44 h60
  text "BLUE" at 12773.46,2742.44 h60
  text "OTHER" at 13311.46,2742.44 h60
  text "X" at 12646,2741 h60
  text "IMMERSION GOLD (ENIG)" at 12393.46,2553.92 h60
  text "ENEPIG" at 13731,2550.64 h60
  text "SURFACE FINISH:" at 11332.46,2549.64 h60
  text "X" at 12206.51,2549.64 h60
  text "IMM. TIN/SILVER OR EQUIV" at 11662,2392.64 h60
  text "OTHER" at 13093.46,2392.64 h60
  text "ARRAY/PANEL:" at 11332.46,2213.64 h60
  text "CUT AND TRIM PER MECH LAYER 1" at 12393.46,2209.35 h60
  text "N.C. ROUTE" at 12393.46,2057.64 h60
  text "X" at 13072.46,2057.64 h60
  text "V. SCORE" at 13259.46,2057.64 h60
  text "CERTIFICATION:" at 11332.46,1920.64 h60
  text "MATERIALS AND WORKMANSHIP FOR ALL PCBS" at 12057.46,1920.64 h60
  text "TO MEET OR EXCEED THE REQUIREMENTS OF:" at 12057.46,1822.64 h60
  text "X" at 11683.96,1686.13 h60
  text "ANSI IPC-A-600F CLASS ->" at 11822.96,1686.13 h60
  text "X" at 13462.02,1686.13 h60
  text "2" at 13580.96,1686.14 h60
  text "1" at 13265.96,1684.64 h60
  text "3" at 13934.96,1684.64 h60
  text "X" at 11686.02,1526.64 h60
  text "UL 94V-0" at 11822.96,1526.64 h60
  text "X" at 12498.02,1526.64 h60
  text "RoHS" at 12634.96,1526.64 h60
  text "OTHER" at 13279.36,1526.64 h60
  text "PER ORDER" at 13676.42,1526.64 h60
  text "ADDITIONAL REQUIREMENTS:" at 11332.46,1385.64 h60
  text "MICROSECTION:" at 11407.23,1270.64 h60
  text "YES" at 12312.96,1270.64 h60
  text "REQUIRED" at 13174.46,1114.49 h60
  text "BARE BOARD ELEC. TEST:" at 11407.23,1111.64 h60
  text "NONE" at 12712.96,1111.64 h60
  text "X" at 13047.46,1111.64 h60
  text "PER ORDER" at 13766.46,1111.64 h60
  text "MANUFACTURER'S UL:" at 11407.23,954.64 h60
  text "RAIL" at 12572.96,950.35 h60
  text "METAL" at 13064.77,950.35 h60
  text "X" at 13440,950 h60
  text "SILK" at 13576.46,950.35 h60
  text ".Layer_Name" at 577,-858.49 h60
M11 Gerber Information:
  lines w10: -292,-930.17 6308,-930.17 ; -292,-726.83 6310,-726.83 ; -292,-523.5 -292,-1133.5 3713,-1133.5 6310,-1133.5 6310,-523.5 -291.5,-523.5 -291.5,-1133.5 1284,-1133.5 ; 2173,-1133.5 2173,-523.5 ; 3440,-726.83 3440,-523.5 ; 4280,-726.83 4280,-523.5 ; 4902,-1140 4902,-937.17
  text "ALL ARTWORK VIEWED FROM TOP SIDE" at -228.5,-655.67 h60
  text "BOARD #:" at 2248,-655.67 h60
  text ".PRJ_Number" at 2793.5,-655.67 h60
  text "REV:" at 3638,-655.67 h60
  text ".PCB_Rev" at 3929.5,-655.67 h60
  text "SVN REV:" at 4476,-655.67 h60
  text ".VersionControl_RevNumber" at 4982,-655.67 h60
  text "LAYER NAME =" at -228.5,-858.49 h60
  text "PLOT NAME =" at -228.5,-1064.34 h60
  text ".plot_File_Name" at 577,-1064.34 h60
  text "GENERATED    :" at 2250,-1064.34 h60
  text ".Print_Date" at 3119.5,-1064.34 h60
  text ".Print_Time" at 3848.5,-1064.34 h60
  text "TEXAS INSTRUMENTS" at 5113,-1064.34 h60
M12 Stackup:
  drawing of 295 lines, arcs and shapes, not listed
  text "Layer" at 8885,7830 h60
  text "Name" at 9294.91,7830 h60
  text "Material" at 11114.37,7830 h60
  text "Thickness" at 11974.14,7830 h60
  text "Constant" at 12623.97,7830 h60
  text "Board Layer Stack" at 13193.83,7830 h60
  text "1" at 8885,7710 h60
  text "Top Overlay" at 9294.91,7710 h60
  text "2" at 8885,7590 h60
  text "Top Solder" at 9294.91,7590 h60
  text "Solder Resist" at 11114.37,7590 h60
  text "0.40mil" at 11974.14,7590 h60
  text "3.5" at 12623.97,7590 h60
  text "3" at 8885,7470 h60
  text "Layer 1 - CIN1 - Top Layer" at 9294.91,7470 h60
  text "Copper" at 11114.37,7470 h60
  text "1.40mil" at 11974.14,7470 h60
  text "4" at 8885,7350 h60
  text "Dielectric1" at 9294.91,7350 h60
  text "370HR" at 11114.37,7350 h60
  text "5.00mil" at 11974.14,7350 h60
  text "4.2" at 12623.97,7350 h60
  text "5" at 8885,7230 h60
  text "Layer 2 - SHLD1 - GND" at 9294.91,7230 h60
  text "Copper" at 11114.37,7230 h60
  text "1.42mil" at 11974.14,7230 h60
  text "6" at 8885,7110 h60
  text "Dielectric 3" at 9294.91,7110 h60
  text "370HR" at 11114.37,7110 h60
  text "45.80mil" at 11974.14,7110 h60
  text "4.2" at 12623.97,7110 h60
  text "7" at 8885,6990 h60
  text "Layer 3 - SHLD2 - PWR" at 9294.91,6990 h60
  text "Copper" at 11114.37,6990 h60
  text "1.42mil" at 11974.14,6990 h60
  text "8" at 8885,6870 h60
  text "Dielectric 2" at 9294.91,6870 h60
  text "370HR" at 11114.37,6870 h60
  text "5.00mil" at 11974.14,6870 h60
  text "4.2" at 12623.97,6870 h60
  text "9" at 8885,6750 h60
  text "Layer 4 - CIN2 - Bottom Layer" at 9294.91,6750 h60
  text "Copper" at 11114.37,6750 h60
  text "1.40mil" at 11974.14,6750 h60
  text "10" at 8885,6630 h60
  text "Bottom Solder" at 9294.91,6630 h60
  text "Solder Resist" at 11114.37,6630 h60
  text "0.40mil" at 11974.14,6630 h60
  text "3.5" at 12623.97,6630 h60
  text "11" at 8885,6510 h60
  text "Bottom Overlay" at 9294.91,6510 h60
  text ".Layer_Name" at 577,-858.49 h60
M13 Component Bodies Top:
  text ".Layer_Name" at 577,-858.49 h60
M14 Component Bodies Bottom:
  text ".Layer_Name" at 577,-858.49 h60
M15 Courtyards Top:
  text ".Layer_Name" at 577,-858.49 h60
M16 Courtyards Bottom:
  text ".Layer_Name" at 577,-858.49 h60
Drill Drawing:
  circle w3.33: c5767.72,3467.4 r24.89
  lines w3.33: 5742.83,2422.16 5767.72,2397.28 5792.6,2422.16 5767.72,2447.05 5742.83,2422.16 ; 5742.83,2546.6 5742.83,2559.04 5755.27,2571.48 5742.83,2583.93 5742.83,2596.37 5755.27,2596.37 5767.72,2583.93 5780.16,2596.37 5792.6,2596.37 5792.6,2583.93 5780.16,2571.48 5792.6,2559.04 5792.6,2546.6 5780.16,2546.6 5767.72,2559.04 5755.27,2546.6 5742.83,2546.6 ; 5742.83,2695.92 5792.6,2695.92 5792.6,2745.69 5742.83,2745.69 5742.83,2695.92 ; 5742.83,2895.01 5792.6,2895.01 5767.72,2845.24 5742.83,2895.01 ; 5742.83,2994.56 5767.72,3007 5792.6,2994.56 5780.16,3019.44 5792.6,3044.33 5767.72,3031.89 5742.83,3044.33 5755.27,3019.44 5742.83,2994.56 ; 5742.83,3193.65 5792.6,3193.65 5767.72,3143.88 5742.83,3193.65 ; 5742.83,3293.2 5792.6,3293.2 5792.6,3342.97 5742.83,3342.97 5742.83,3293.2 ; 5742.83,3591.84 5767.72,3604.28 5792.6,3591.84 5780.16,3616.72 5792.6,3641.61 5767.72,3629.17 5742.83,3641.61 5755.27,3616.72 5742.83,3591.84 ; 5742.83,3753.6 5755.27,3753.6 5755.27,3741.16 5780.16,3741.16 5780.16,3753.6 5792.6,3753.6 5792.6,3778.49 5780.16,3778.49 5780.16,3790.93 5755.27,3790.93 5755.27,3778.49 5742.83,3778.49 5742.83,3753.6 ; 5752.78,2885.05 5782.65,2885.05 5767.72,2855.19 5752.78,2885.05 ; 5752.78,3303.15 5782.65,3303.15 5782.65,3333.01 5752.78,3333.01 5752.78,3303.15 ; 5752.78,3601.79 5767.72,3609.26 5782.65,3601.79 5775.18,3616.72 5782.65,3631.65 5767.72,3624.19 5752.78,3631.65 5760.25,3616.72 5752.78,3601.79
  lines w12: 5675,2352.48 7793.02,2352.48 ; 5675,3845.68 7793.02,3845.68 ; 6045.36,2203.16 6045.36,3995 ; 6402.36,2203.16 6402.36,3995 ; 7063.93,2203.16 7063.93,3995 ; 7348.07,2203.16 7348.07,3995 ; 5675,2203.16 7793.02,2203.16 7793.02,3995 5675,3995 5675,2203.16
  text "Symbol" at 5764.59,3890.48 h72
  text "Quantity" at 6090.16,3890.48 h72
  text "Finished Hole Size" at 6447.16,3890.48 h72
  text "Plated" at 7108.72,3890.48 h72
  text "Hole Type" at 7392.86,3890.48 h72
  text "4" at 6090.16,3741.16 h60
  text "57.09mil (1.450mm)" at 6447.16,3741.16 h60
  text "NPTH" at 7108.72,3741.16 h60
  text "Round" at 7392.86,3741.16 h60
  text "2" at 6090.16,3591.84 h60
  text "96.00mil (2.438mm)" at 6447.16,3591.84 h60
  text "NPTH" at 7108.72,3591.84 h60
  text "Round" at 7392.86,3591.84 h60
  text "13" at 6090.16,3442.52 h60
  text "7.87mil (0.200mm)" at 6447.16,3442.52 h60
  text "PTH" at 7108.72,3442.52 h60
  text "Round" at 7392.86,3442.52 h60
  text "151" at 6090.16,3293.2 h60
  text "10.00mil (0.254mm)" at 6447.16,3293.2 h60
  text "PTH" at 7108.72,3293.2 h60
  text "Round" at 7392.86,3293.2 h60
  text "26" at 6090.16,3143.88 h60
  text "31.50mil (0.800mm)" at 6447.16,3143.88 h60
  text "PTH" at 7108.72,3143.88 h60
  text "Round" at 7392.86,3143.88 h60
  text "8" at 6090.16,2994.56 h60
  text "40.00mil (1.016mm)" at 6447.16,2994.56 h60
  text "PTH" at 7108.72,2994.56 h60
  text "Round" at 7392.86,2994.56 h60
  text "2" at 6090.16,2845.24 h60
  text "63.00mil (1.600mm)" at 6447.16,2845.24 h60
  text "PTH" at 7108.72,2845.24 h60
  text "Round" at 7392.86,2845.24 h60
  text "4" at 6090.16,2695.92 h60
  text "125.98mil (3.200mm)" at 6447.16,2695.92 h60
  text "PTH" at 7108.72,2695.92 h60
  text "Round" at 7392.86,2695.92 h60
  text "2" at 6090.16,2546.6 h60
  text "19.69mil (0.500mm)" at 6447.16,2546.6 h60
  text "PTH" at 7108.72,2546.6 h60
  text "Slot" at 7392.86,2546.6 h60
  text "1" at 6090.16,2397.28 h60
  text "19.69mil (0.500mm)" at 6447.16,2397.28 h60
  text "PTH" at 7108.72,2397.28 h60
  text "Slot" at 7392.86,2397.28 h60
  text "213 Total" at 6090.16,2247.96 h60
  text ".Layer_Name" at 577,-858.49 h60

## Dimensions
0,-400 to 1000,-400 on M2 Board Dimensions
0,0 to 0,4000 on M2 Board Dimensions
0,0 to 5000,0 on M2 Board Dimensions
